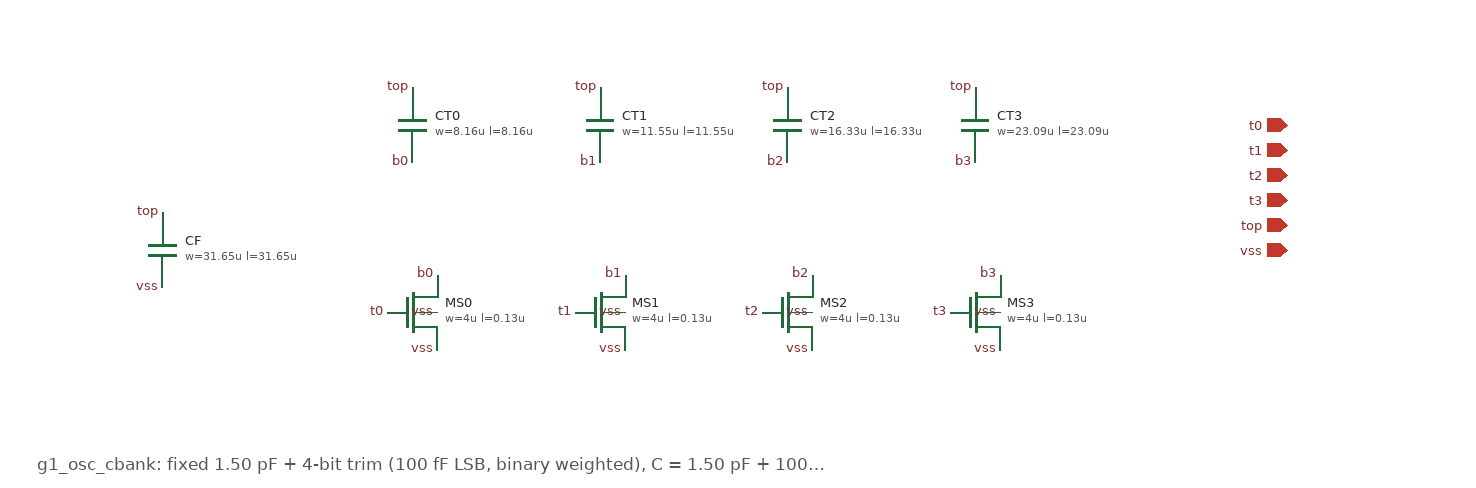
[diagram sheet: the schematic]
v {xschem version=3.4.8RC file_version=1.3}
G {}
K {}
V {}
S {}
E {}
T {g1_osc_cbank: fixed 1.50 pF + 4-bit trim (100 fF LSB, binary weighted), C = 1.50 pF + 100 fF * code} 0 -40 0 0 0.4 0.4 {}
C {sg13g2_pr/cap_cmim.sym} 100 -200 0 0 {name=CF model=cap_cmim w=31.65u l=31.65u m=1}
C {devices/lab_pin.sym} 100 -230 0 0 {name=l1 lab=top}
C {devices/lab_pin.sym} 100 -170 0 0 {name=l2 lab=vss}
C {sg13g2_pr/cap_cmim.sym} 300 -300 0 0 {name=CT0 model=cap_cmim w=8.16u l=8.16u m=1}
C {devices/lab_pin.sym} 300 -330 0 0 {name=l3 lab=top}
C {devices/lab_pin.sym} 300 -270 0 0 {name=l4 lab=b0}
C {sg13g2_pr/sg13_lv_nmos.sym} 300 -150 0 0 {name=MS0 model=sg13_lv_nmos w=4u l=0.13u ng=1 m=1}
C {devices/lab_pin.sym} 320 -180 0 0 {name=l5 lab=b0}
C {devices/lab_pin.sym} 280 -150 0 0 {name=l6 lab=t0}
C {devices/lab_pin.sym} 320 -120 0 0 {name=l7 lab=vss}
C {devices/lab_pin.sym} 320 -150 0 0 {name=l8 lab=vss}
C {sg13g2_pr/cap_cmim.sym} 450 -300 0 0 {name=CT1 model=cap_cmim w=11.55u l=11.55u m=1}
C {devices/lab_pin.sym} 450 -330 0 0 {name=l9 lab=top}
C {devices/lab_pin.sym} 450 -270 0 0 {name=l10 lab=b1}
C {sg13g2_pr/sg13_lv_nmos.sym} 450 -150 0 0 {name=MS1 model=sg13_lv_nmos w=4u l=0.13u ng=1 m=1}
C {devices/lab_pin.sym} 470 -180 0 0 {name=l11 lab=b1}
C {devices/lab_pin.sym} 430 -150 0 0 {name=l12 lab=t1}
C {devices/lab_pin.sym} 470 -120 0 0 {name=l13 lab=vss}
C {devices/lab_pin.sym} 470 -150 0 0 {name=l14 lab=vss}
C {sg13g2_pr/cap_cmim.sym} 600 -300 0 0 {name=CT2 model=cap_cmim w=16.33u l=16.33u m=1}
C {devices/lab_pin.sym} 600 -330 0 0 {name=l15 lab=top}
C {devices/lab_pin.sym} 600 -270 0 0 {name=l16 lab=b2}
C {sg13g2_pr/sg13_lv_nmos.sym} 600 -150 0 0 {name=MS2 model=sg13_lv_nmos w=4u l=0.13u ng=1 m=1}
C {devices/lab_pin.sym} 620 -180 0 0 {name=l17 lab=b2}
C {devices/lab_pin.sym} 580 -150 0 0 {name=l18 lab=t2}
C {devices/lab_pin.sym} 620 -120 0 0 {name=l19 lab=vss}
C {devices/lab_pin.sym} 620 -150 0 0 {name=l20 lab=vss}
C {sg13g2_pr/cap_cmim.sym} 750 -300 0 0 {name=CT3 model=cap_cmim w=23.09u l=23.09u m=1}
C {devices/lab_pin.sym} 750 -330 0 0 {name=l21 lab=top}
C {devices/lab_pin.sym} 750 -270 0 0 {name=l22 lab=b3}
C {sg13g2_pr/sg13_lv_nmos.sym} 750 -150 0 0 {name=MS3 model=sg13_lv_nmos w=4u l=0.13u ng=1 m=1}
C {devices/lab_pin.sym} 770 -180 0 0 {name=l23 lab=b3}
C {devices/lab_pin.sym} 730 -150 0 0 {name=l24 lab=t3}
C {devices/lab_pin.sym} 770 -120 0 0 {name=l25 lab=vss}
C {devices/lab_pin.sym} 770 -150 0 0 {name=l26 lab=vss}
C {devices/ipin.sym} 1000 -300 0 0 {name=pi0 lab=t0}
C {devices/ipin.sym} 1000 -280 0 0 {name=pi1 lab=t1}
C {devices/ipin.sym} 1000 -260 0 0 {name=pi2 lab=t2}
C {devices/ipin.sym} 1000 -240 0 0 {name=pi3 lab=t3}
C {devices/iopin.sym} 1000 -220 0 0 {name=pb0 lab=top}
C {devices/iopin.sym} 1000 -200 0 0 {name=pb1 lab=vss}
